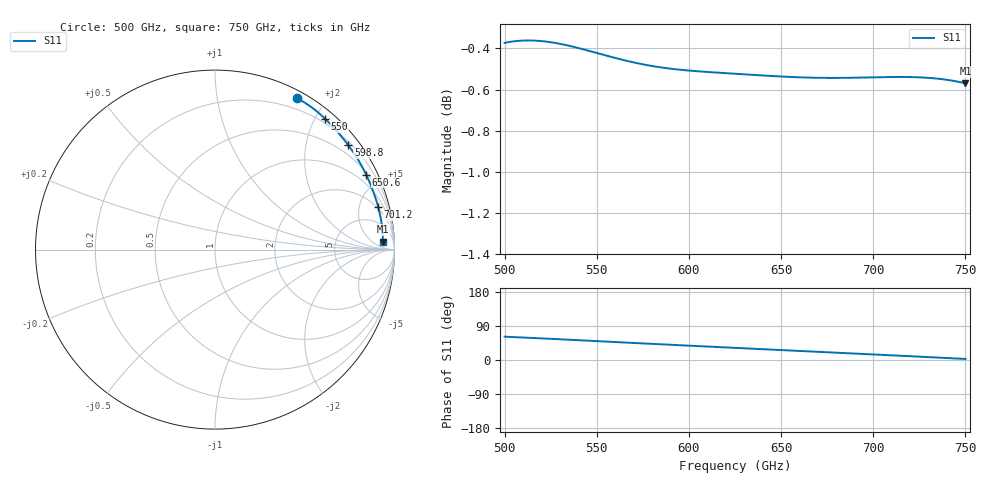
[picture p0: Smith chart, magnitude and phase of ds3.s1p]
!Created with skrf (http://scikit-rf.org).
# GHz S RI R 50.0
!freq ReS11 ImS11
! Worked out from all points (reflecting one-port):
!   401 points, 500 GHz to 750 GHz, reference 50 ohm
!   lowest |S11| = -0.6 dB at 750 GHz (marker M1), VSWR 30.50, Z = 992 + j727 ohm
!   phase of S11 starts at 62 deg and turns -59 deg over the sweep
!   S11 on the Smith chart (normalised r, x): 500 GHz: 0.08, +1.68; 550 GHz: 0.14, +2.14; 598.8 GHz: 0.27, +2.87; 650.6 GHz: 0.58, +4.19; 701.2 GHz: 1.84, +7.40; 750 GHz: 20, +15
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500  0.4564 0.8422
501.25  0.4605 0.8403
506.25  0.4768 0.832
514.375  0.5031 0.8167
522.5  0.5293 0.7993
531.25  0.5569 0.7785
540  0.5839 0.7559
550  0.6139 0.7284
562.5  0.6498 0.692
570.625  0.6721 0.6677
578.75  0.6936 0.643
593.75  0.7309 0.5972
598.75  0.7425 0.5818
611.875  0.7713 0.5414
625  0.7975 0.5004
637.5  0.8203 0.4606
650.625  0.8423 0.4174
656.25  0.8511 0.3985
672.5  0.8749 0.342
687.5  0.8943 0.2875
701.25  0.9096 0.2358
710  0.9178 0.2021
718.75  0.9247 0.1679
726.875  0.9297 0.1359
735  0.9332 0.1038
741.875  0.9349 0.0767
748.75  0.9355 0.0499
750  0.9354 0.045
